# Generated by FakeRAM 2.0
VERSION 5.7 ;
BUSBITCHARS "[]" ;
PROPERTYDEFINITIONS
  MACRO width INTEGER ;
  MACRO depth INTEGER ;
  MACRO banks INTEGER ;
END PROPERTYDEFINITIONS
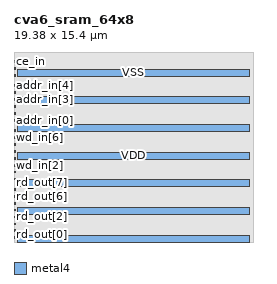
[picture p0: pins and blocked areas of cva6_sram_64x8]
MACRO cva6_sram_64x8
  PROPERTY width 8 ;
  PROPERTY depth 64 ;
  PROPERTY banks 1 ;
  FOREIGN cva6_sram_64x8 0 0 ;
  SYMMETRY X Y R90 ;
  SIZE 19.3800 BY 15.4000 ;
  CLASS BLOCK ;
  PIN rd_out[0]
    DIRECTION OUTPUT ;
    USE SIGNAL ;
    PORT
      LAYER metal4 ;
      RECT 0.00000 0.28000 0.14000 0.42000 ;
    END
  END rd_out[0]
  PIN rd_out[1]
    DIRECTION OUTPUT ;
    USE SIGNAL ;
    PORT
      LAYER metal4 ;
      RECT 0.00000 0.84000 0.14000 0.98000 ;
    END
  END rd_out[1]
  PIN rd_out[2]
    DIRECTION OUTPUT ;
    USE SIGNAL ;
    PORT
      LAYER metal4 ;
      RECT 0.00000 1.40000 0.14000 1.54000 ;
    END
  END rd_out[2]
  PIN rd_out[3]
    DIRECTION OUTPUT ;
    USE SIGNAL ;
    PORT
      LAYER metal4 ;
      RECT 0.00000 1.96000 0.14000 2.10000 ;
    END
  END rd_out[3]
  PIN rd_out[4]
    DIRECTION OUTPUT ;
    USE SIGNAL ;
    PORT
      LAYER metal4 ;
      RECT 0.00000 2.52000 0.14000 2.66000 ;
    END
  END rd_out[4]
  PIN rd_out[5]
    DIRECTION OUTPUT ;
    USE SIGNAL ;
    PORT
      LAYER metal4 ;
      RECT 0.00000 3.08000 0.14000 3.22000 ;
    END
  END rd_out[5]
  PIN rd_out[6]
    DIRECTION OUTPUT ;
    USE SIGNAL ;
    PORT
      LAYER metal4 ;
      RECT 0.00000 3.64000 0.14000 3.78000 ;
    END
  END rd_out[6]
  PIN rd_out[7]
    DIRECTION OUTPUT ;
    USE SIGNAL ;
    PORT
      LAYER metal4 ;
      RECT 0.00000 4.20000 0.14000 4.34000 ;
    END
  END rd_out[7]
  PIN wd_in[0]
    DIRECTION INPUT ;
    USE SIGNAL ;
    PORT
      LAYER metal4 ;
      RECT 0.00000 5.04000 0.14000 5.18000 ;
    END
  END wd_in[0]
  PIN wd_in[1]
    DIRECTION INPUT ;
    USE SIGNAL ;
    PORT
      LAYER metal4 ;
      RECT 0.00000 5.60000 0.14000 5.74000 ;
    END
  END wd_in[1]
  PIN wd_in[2]
    DIRECTION INPUT ;
    USE SIGNAL ;
    PORT
      LAYER metal4 ;
      RECT 0.00000 6.16000 0.14000 6.30000 ;
    END
  END wd_in[2]
  PIN wd_in[3]
    DIRECTION INPUT ;
    USE SIGNAL ;
    PORT
      LAYER metal4 ;
      RECT 0.00000 6.72000 0.14000 6.86000 ;
    END
  END wd_in[3]
  PIN wd_in[4]
    DIRECTION INPUT ;
    USE SIGNAL ;
    PORT
      LAYER metal4 ;
      RECT 0.00000 7.28000 0.14000 7.42000 ;
    END
  END wd_in[4]
  PIN wd_in[5]
    DIRECTION INPUT ;
    USE SIGNAL ;
    PORT
      LAYER metal4 ;
      RECT 0.00000 7.84000 0.14000 7.98000 ;
    END
  END wd_in[5]
  PIN wd_in[6]
    DIRECTION INPUT ;
    USE SIGNAL ;
    PORT
      LAYER metal4 ;
      RECT 0.00000 8.40000 0.14000 8.54000 ;
    END
  END wd_in[6]
  PIN wd_in[7]
    DIRECTION INPUT ;
    USE SIGNAL ;
    PORT
      LAYER metal4 ;
      RECT 0.00000 8.96000 0.14000 9.10000 ;
    END
  END wd_in[7]
  PIN addr_in[0]
    DIRECTION INPUT ;
    USE SIGNAL ;
    PORT
      LAYER metal4 ;
      RECT 0.00000 9.80000 0.14000 9.94000 ;
    END
  END addr_in[0]
  PIN addr_in[1]
    DIRECTION INPUT ;
    USE SIGNAL ;
    PORT
      LAYER metal4 ;
      RECT 0.00000 10.36000 0.14000 10.50000 ;
    END
  END addr_in[1]
  PIN addr_in[2]
    DIRECTION INPUT ;
    USE SIGNAL ;
    PORT
      LAYER metal4 ;
      RECT 0.00000 10.92000 0.14000 11.06000 ;
    END
  END addr_in[2]
  PIN addr_in[3]
    DIRECTION INPUT ;
    USE SIGNAL ;
    PORT
      LAYER metal4 ;
      RECT 0.00000 11.48000 0.14000 11.62000 ;
    END
  END addr_in[3]
  PIN addr_in[4]
    DIRECTION INPUT ;
    USE SIGNAL ;
    PORT
      LAYER metal4 ;
      RECT 0.00000 12.04000 0.14000 12.18000 ;
    END
  END addr_in[4]
  PIN addr_in[5]
    DIRECTION INPUT ;
    USE SIGNAL ;
    PORT
      LAYER metal4 ;
      RECT 0.00000 12.60000 0.14000 12.74000 ;
    END
  END addr_in[5]
  PIN we_in
    DIRECTION INPUT ;
    USE SIGNAL ;
    PORT
      LAYER metal4 ;
      RECT 0.00000 13.44000 0.14000 13.58000 ;
    END
  END we_in
  PIN clk
    DIRECTION INPUT ;
    USE SIGNAL ;
    PORT
      LAYER metal4 ;
      RECT 0.00000 14.00000 0.14000 14.14000 ;
    END
  END clk
  PIN ce_in
    DIRECTION INPUT ;
    USE SIGNAL ;
    PORT
      LAYER metal4 ;
      RECT 0.00000 14.56000 0.14000 14.70000 ;
    END
  END ce_in
  PIN VDD
    DIRECTION INOUT ;
    USE POWER ;
    PORT
      LAYER metal4 ;
      RECT 0.28000 2.24000 19.10000 2.80000 ;
      RECT 0.28000 6.72000 19.10000 7.28000 ;
      RECT 0.28000 11.20000 19.10000 11.76000 ;
    END
  END VDD
  PIN VSS
    DIRECTION INOUT ;
    USE GROUND ;
    PORT
      LAYER metal4 ;
      RECT 0.28000 0.00000 19.10000 0.56000 ;
      RECT 0.28000 4.48000 19.10000 5.04000 ;
      RECT 0.28000 8.96000 19.10000 9.52000 ;
      RECT 0.28000 13.44000 19.10000 14.00000 ;
    END
  END VSS
  OBS
    LAYER metal1 ;
    RECT 0 0 19.38000 15.40000 ;
    LAYER metal2 ;
    RECT 0 0 19.38000 15.40000 ;
    LAYER metal3 ;
    RECT 0 0 19.38000 15.40000 ;
    LAYER metal4 ;
    RECT 0 0 19.38000 15.40000 ;
  END
END cva6_sram_64x8

END LIBRARY
